VERSION 5.8 ;
BUSBITCHARS "[]" ;
DIVIDERCHAR "/" ;
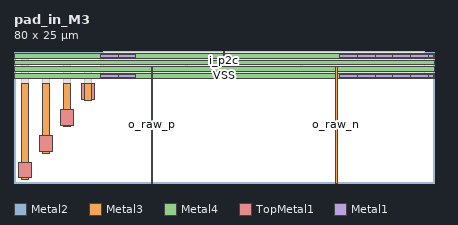
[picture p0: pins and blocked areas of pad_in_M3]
MACRO pad_in_M3
  CLASS BLOCK ;
  FOREIGN pad_in_M3 0 0 ;
  ORIGIN 0.000 0.000 ;
  SIZE 80.000 BY 25.000 ;
  SYMMETRY X Y R90 ;
  PIN i_p2c
    DIRECTION INPUT ;
    PORT
      LAYER Metal2 ;
        RECT 39.850 24.200 40.150 25.000 ;
    END
  END i_p2c
  PIN i_clk_p
    DIRECTION INPUT ;
    PORT
      LAYER Metal3 ;
        RECT 9.500 10.700 10.700 19.000 ;
      LAYER Metal4 ;
        RECT 0.000 22.500 80.000 23.300 ;
      LAYER TopMetal1 ;
        RECT 8.950 11.000 11.250 14.000 ;
    END
  END i_clk_p
  PIN i_clk_n
    DIRECTION INPUT ;
    PORT
      LAYER Metal3 ;
        RECT 13.500 15.700 14.700 19.000 ;
      LAYER Metal4 ;
        RECT 0.000 21.300 80.000 22.100 ;
      LAYER TopMetal1 ;
        RECT 12.950 16.000 15.250 19.000 ;
    END
  END i_clk_n
  PIN o_raw_p
    DIRECTION OUTPUT ;
    PORT
      LAYER Metal3 ;
        RECT 26.110 0.000 26.410 22.275 ;
    END
  END o_raw_p
  PIN o_raw_n
    DIRECTION OUTPUT ;
    PORT
      LAYER Metal3 ;
        RECT 61.270 0.000 61.570 22.275 ;
    END
  END o_raw_n
  PIN VDD
    DIRECTION INOUT ;
    USE POWER ;
    PORT
      LAYER Metal1 ;
        RECT 16.480 23.960 19.840 24.400 ;
      LAYER Metal1 ;
        RECT 19.840 23.960 23.200 24.400 ;
      LAYER Metal1 ;
        RECT 62.080 23.960 65.440 24.400 ;
      LAYER Metal1 ;
        RECT 65.440 23.960 68.800 24.400 ;
      LAYER Metal1 ;
        RECT 68.800 23.960 72.160 24.400 ;
      LAYER Metal1 ;
        RECT 72.160 23.960 75.520 24.400 ;
      LAYER Metal1 ;
        RECT 75.520 23.960 78.880 24.400 ;
      LAYER Metal1 ;
        RECT 78.880 23.960 79.840 24.400 ;
      LAYER Metal3 ;
        RECT 1.500 0.700 2.700 19.000 ;
      LAYER Metal4 ;
        RECT 0.000 23.780 80.000 24.580 ;
      LAYER TopMetal1 ;
        RECT 0.950 1.000 3.250 4.000 ;
    END
  END VDD
  PIN VSS
    DIRECTION INOUT ;
    USE GROUND ;
    PORT
      LAYER Metal1 ;
        RECT 16.480 20.180 19.840 20.620 ;
      LAYER Metal1 ;
        RECT 19.840 20.180 23.200 20.620 ;
      LAYER Metal1 ;
        RECT 62.080 20.180 65.440 20.620 ;
      LAYER Metal1 ;
        RECT 65.440 20.180 68.800 20.620 ;
      LAYER Metal1 ;
        RECT 68.800 20.180 72.160 20.620 ;
      LAYER Metal1 ;
        RECT 72.160 20.180 75.520 20.620 ;
      LAYER Metal1 ;
        RECT 75.520 20.180 78.880 20.620 ;
      LAYER Metal1 ;
        RECT 78.880 20.180 79.840 20.620 ;
      LAYER Metal3 ;
        RECT 5.500 5.700 6.700 19.000 ;
      LAYER Metal4 ;
        RECT 0.000 20.000 80.000 20.800 ;
      LAYER TopMetal1 ;
        RECT 4.950 6.000 7.250 9.000 ;
    END
  END VSS
  OBS
    LAYER Metal1 ;
      RECT 16.480 20.620 23.200 23.960 ;
      RECT 62.080 20.620 79.840 23.960 ;
      RECT 23.200 20.180 62.080 24.400 ;
    LAYER Metal2 ;
      RECT 17.085 24.200 39.850 25.000 ;
      RECT 40.150 20.205 78.215 25.000 ;
      RECT 17.085 20.205 40.150 24.200 ;
    LAYER Metal3 ;
      RECT 17.085 20.205 17.475 20.595 ;
      RECT 18.785 20.205 19.175 20.595 ;
      RECT 20.445 20.205 20.835 20.595 ;
      RECT 22.145 20.205 22.535 20.595 ;
      RECT 30.925 20.205 31.315 20.595 ;
      RECT 35.725 20.205 36.115 20.595 ;
      RECT 40.525 20.205 40.915 20.595 ;
      RECT 45.085 20.205 45.475 20.595 ;
      RECT 47.005 20.205 47.395 20.595 ;
      RECT 51.565 20.205 51.955 20.595 ;
      RECT 56.365 20.205 56.755 20.595 ;
      RECT 62.685 20.205 63.075 20.595 ;
      RECT 64.385 20.205 64.775 20.595 ;
      RECT 66.045 20.205 66.435 20.595 ;
      RECT 67.745 20.205 68.135 20.595 ;
      RECT 69.405 20.205 69.795 20.595 ;
      RECT 71.105 20.205 71.495 20.595 ;
      RECT 72.765 20.205 73.155 20.595 ;
      RECT 74.465 20.205 74.855 20.595 ;
      RECT 76.125 20.205 76.515 20.595 ;
      RECT 77.825 20.205 78.215 20.595 ;
      RECT 5.500 19.000 6.700 20.700 ;
      RECT 13.500 19.000 14.700 22.000 ;
      RECT 9.500 19.000 10.700 23.200 ;
      RECT 32.750 21.895 33.050 23.315 ;
      RECT 32.705 21.505 33.095 21.895 ;
      RECT 37.505 22.925 37.895 23.315 ;
      RECT 42.350 21.895 42.650 23.315 ;
      RECT 42.305 21.505 42.695 21.895 ;
      RECT 49.785 22.925 50.175 23.315 ;
      RECT 54.630 21.895 54.930 23.315 ;
      RECT 54.585 21.505 54.975 21.895 ;
      RECT 17.085 23.985 17.475 24.375 ;
      RECT 18.785 23.985 19.175 24.375 ;
      RECT 20.445 23.985 20.835 24.375 ;
      RECT 22.145 23.985 22.535 24.375 ;
      RECT 32.125 23.985 32.515 24.375 ;
      RECT 36.925 23.985 37.315 24.375 ;
      RECT 41.725 23.985 42.115 24.375 ;
      RECT 45.085 23.985 45.475 24.375 ;
      RECT 47.005 23.985 47.395 24.375 ;
      RECT 50.365 23.985 50.755 24.375 ;
      RECT 55.165 23.985 55.555 24.375 ;
      RECT 62.685 23.985 63.075 24.375 ;
      RECT 64.385 23.985 64.775 24.375 ;
      RECT 66.045 23.985 66.435 24.375 ;
      RECT 67.745 23.985 68.135 24.375 ;
      RECT 69.405 23.985 69.795 24.375 ;
      RECT 71.105 23.985 71.495 24.375 ;
      RECT 72.765 23.985 73.155 24.375 ;
      RECT 74.465 23.985 74.855 24.375 ;
      RECT 76.125 23.985 76.515 24.375 ;
      RECT 77.825 23.985 78.215 24.375 ;
      RECT 1.500 19.000 2.700 24.480 ;
    LAYER Metal4 ;
      RECT 1.350 1.700 2.850 3.300 ;
      RECT 5.350 6.700 6.850 8.300 ;
      RECT 9.350 11.700 10.850 13.300 ;
      RECT 13.350 16.700 14.850 18.300 ;
  END
END pad_in_M3

END LIBRARY
